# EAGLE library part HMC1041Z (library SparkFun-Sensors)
Honeywell 1-axis magnetometer

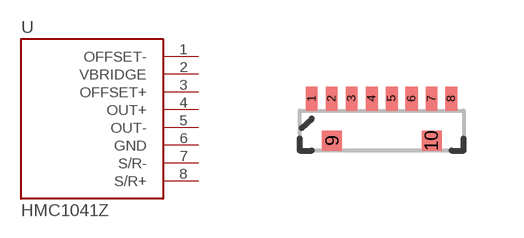
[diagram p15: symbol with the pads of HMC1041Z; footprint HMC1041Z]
Designator prefix -

## HMC1041Z  [HMC1041Z]
1  OFFSET-
2  VBRIDGE
3  OFFSET+
4  OUT+
5  OUT-
6  GND
7  S/R-
8  S/R+

## Footprint HMC1041Z (pad centres in mm)
smd 0.3 x 0.6: 1 -1.75,0; 2 -1.25,0; 3 -0.75,0; 4 -0.25,0; 5 0.25,0; 6 0.75,0; 7 1.25,0; 8 1.74,0
smd 0.5 x 0.5: 9 -1.25,-1.05; 10 1.25,-1.05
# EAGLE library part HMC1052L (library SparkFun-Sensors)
HMC1052L Dual axis magnetic sensor. Used for compass and magnetometer applications. Schematic and footprint are not tested and probably need fixing. Spark Fun Electronics SKU : COM-00708

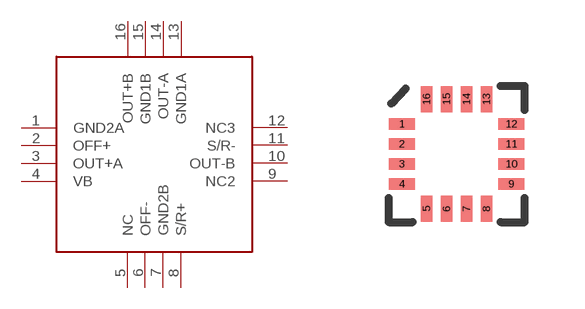
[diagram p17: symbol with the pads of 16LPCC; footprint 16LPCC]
Designator prefix -

## HMC1052L  [16LPCC]
1  GND2A
2  OFF+
3  OUT+A
4  VB
5  NC
6  OFF-
7  GND2B
8  S/R+
9  NC2
10  OUT-B
11  S/R-
12  NC3
13  GND1A
14  OUT-A
15  GND1B
16  OUT+B

## Footprint 16LPCC (pad centres in mm)
smd 0.65 x 0.28: 1 -1.37,0.75; 2 -1.37,0.25; 3 -1.37,-0.25; 4 -1.37,-0.75; 9 1.37,-0.75; 10 1.37,-0.25; 11 1.37,0.25; 12 1.37,0.75
smd 0.28 x 0.65: 5 -0.75,-1.37; 6 -0.25,-1.37; 7 0.25,-1.37; 8 0.75,-1.37; 13 0.75,1.37; 14 0.25,1.37; 15 -0.25,1.37; 16 -0.75,1.37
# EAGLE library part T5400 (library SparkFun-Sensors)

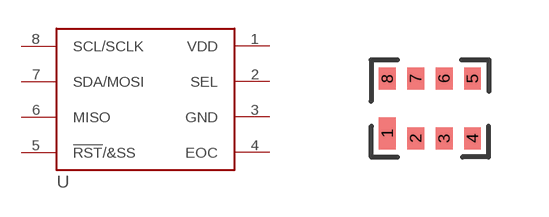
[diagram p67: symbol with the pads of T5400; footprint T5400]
Designator prefix U

## T5400 (PROD_ID: IC-11772)  [T5400]
1  VDD
2  SEL
3  GND
4  EOC
5  !RST!/&SS
6  MISO
7  SDA/MOSI
8  SCL/SCLK

## Footprint T5400 (pad centres in mm)
smd 0.42 x 0.8: 1 -1.065,-0.625
smd 0.42 x 0.55: 2 -0.355,-0.75; 3 0.355,-0.75; 4 1.065,-0.75; 5 1.065,0.75; 6 0.355,0.75; 7 -0.355,0.75; 8 -1.065,0.75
